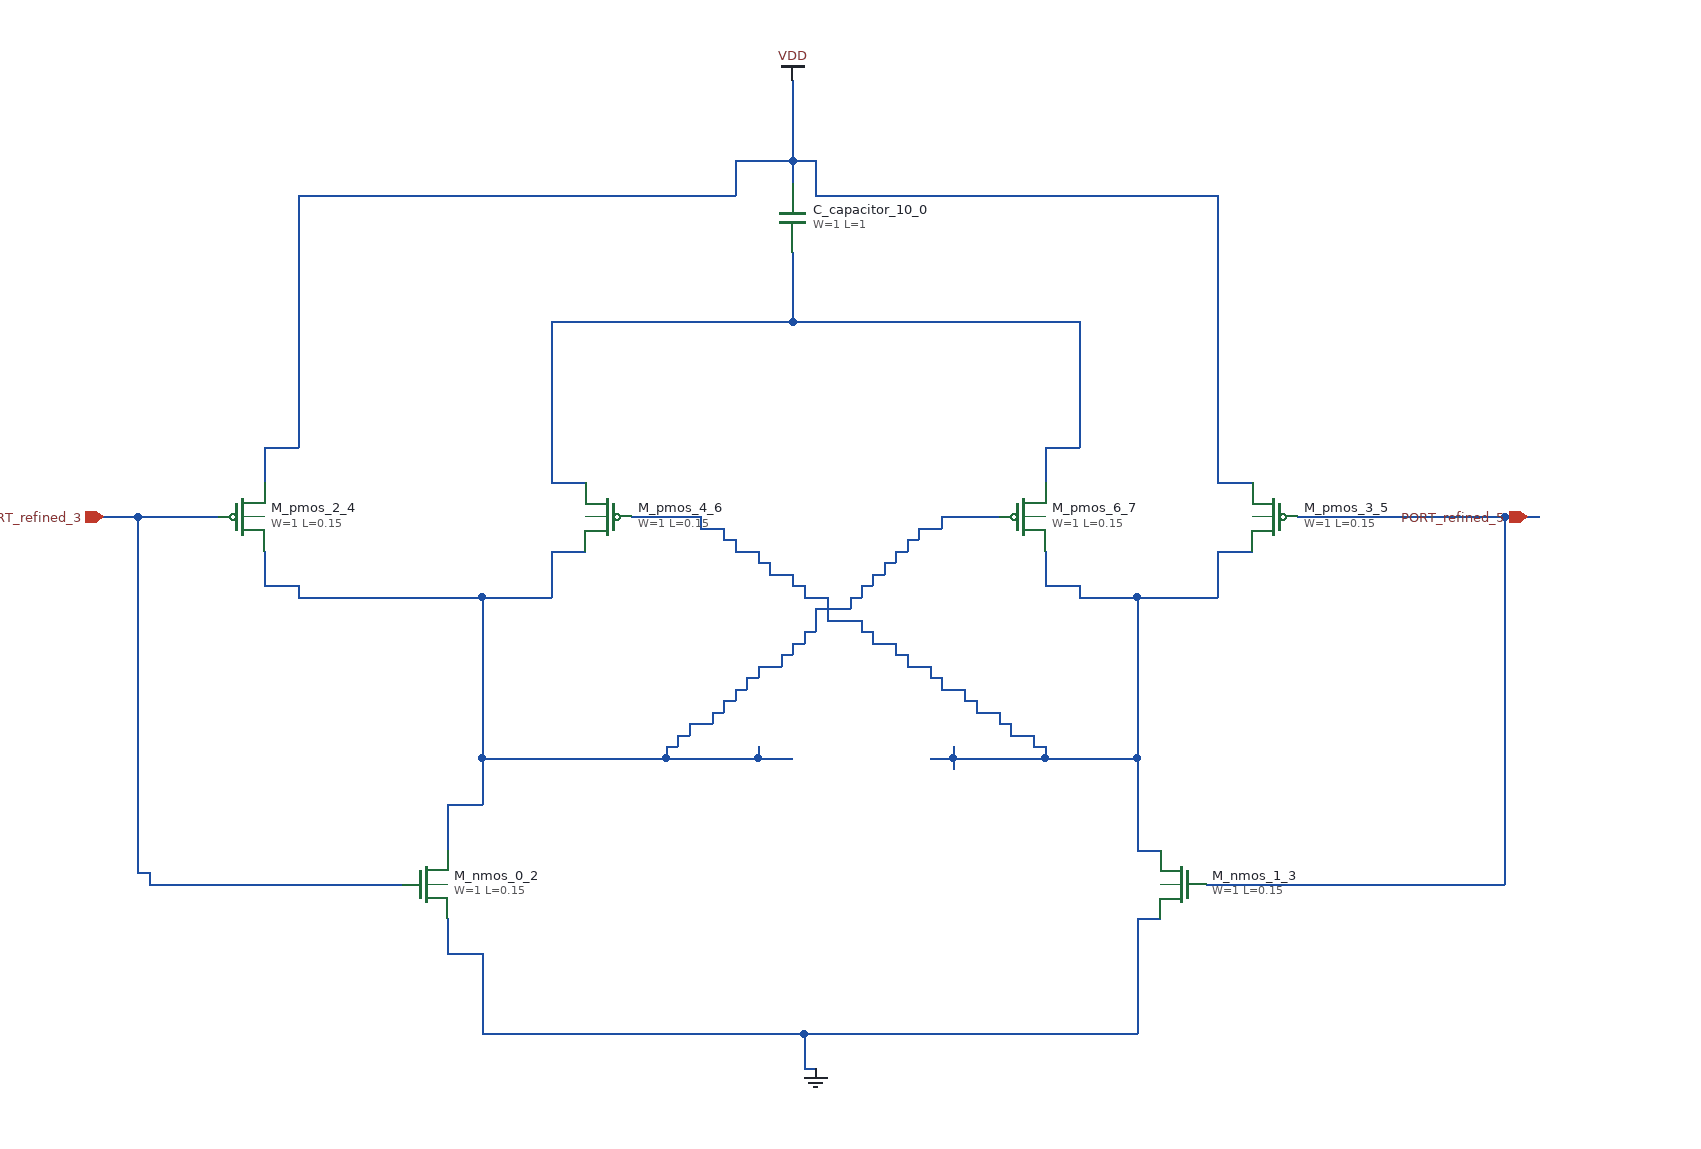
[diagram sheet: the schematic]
v {xschem version=3.4.8 file_version=1.2}
G {}
K {}
V {}
S {}
E {}
C {sky130_fd_pr/cap_mim_m3_1.sym} 680 200 2 0 {name="C_capacitor_10_0" model=cap_mim_m3_1 W=1 L=1 MF=1 spiceprefix=X}
C {devices/gnd.sym} 700 940 0 0 {name="l_gnd_5_1" lab="GND"}
C {sky130_fd_pr/nfet3_01v8.sym} 360 780 0 0 {name="M_nmos_0_2"
W=1
L=0.15
body=GND
nf=1
mult=1
ad="expr('int((@nf + 1)/2) * @W / @nf * 0.29')"
pd="expr('2*int((@nf + 1)/2) * (@W / @nf + 0.29)')"
as="expr('int((@nf + 2)/2) * @W / @nf * 0.29')"
ps="expr('2*int((@nf + 2)/2) * (@W / @nf + 0.29)')"
nrd="expr('0.29 / @W ')" nrs="expr('0.29 / @W ')"
sa=0 sb=0 sd=0
model=nfet_01v8
spiceprefix=X
}
C {sky130_fd_pr/nfet3_01v8.sym} 1020 780 0 1 {name="M_nmos_1_3"
W=1
L=0.15
body=GND
nf=1
mult=1
ad="expr('int((@nf + 1)/2) * @W / @nf * 0.29')"
pd="expr('2*int((@nf + 1)/2) * (@W / @nf + 0.29)')"
as="expr('int((@nf + 2)/2) * @W / @nf * 0.29')"
ps="expr('2*int((@nf + 2)/2) * (@W / @nf + 0.29)')"
nrd="expr('0.29 / @W ')" nrs="expr('0.29 / @W ')"
sa=0 sb=0 sd=0
model=nfet_01v8
spiceprefix=X
}
C {sky130_fd_pr/pfet3_01v8.sym} 200 460 0 0 {name="M_pmos_2_4"
W=1
L=0.15
body=VDD
nf=1
mult=1
ad="expr('int((@nf + 1)/2) * @W / @nf * 0.29')"
pd="expr('2*int((@nf + 1)/2) * (@W / @nf + 0.29)')"
as="expr('int((@nf + 2)/2) * @W / @nf * 0.29')"
ps="expr('2*int((@nf + 2)/2) * (@W / @nf + 0.29)')"
nrd="expr('0.29 / @W ')" nrs="expr('0.29 / @W ')"
sa=0 sb=0 sd=0
model=pfet_01v8
spiceprefix=X
}
C {sky130_fd_pr/pfet3_01v8.sym} 1100 460 0 1 {name="M_pmos_3_5"
W=1
L=0.15
body=VDD
nf=1
mult=1
ad="expr('int((@nf + 1)/2) * @W / @nf * 0.29')"
pd="expr('2*int((@nf + 1)/2) * (@W / @nf + 0.29)')"
as="expr('int((@nf + 2)/2) * @W / @nf * 0.29')"
ps="expr('2*int((@nf + 2)/2) * (@W / @nf + 0.29)')"
nrd="expr('0.29 / @W ')" nrs="expr('0.29 / @W ')"
sa=0 sb=0 sd=0
model=pfet_01v8
spiceprefix=X
}
C {sky130_fd_pr/pfet3_01v8.sym} 520 460 0 1 {name="M_pmos_4_6"
W=1
L=0.15
body=VDD
nf=1
mult=1
ad="expr('int((@nf + 1)/2) * @W / @nf * 0.29')"
pd="expr('2*int((@nf + 1)/2) * (@W / @nf + 0.29)')"
as="expr('int((@nf + 2)/2) * @W / @nf * 0.29')"
ps="expr('2*int((@nf + 2)/2) * (@W / @nf + 0.29)')"
nrd="expr('0.29 / @W ')" nrs="expr('0.29 / @W ')"
sa=0 sb=0 sd=0
model=pfet_01v8
spiceprefix=X
}
C {sky130_fd_pr/pfet3_01v8.sym} 880 460 0 0 {name="M_pmos_6_7"
W=1
L=0.15
body=VDD
nf=1
mult=1
ad="expr('int((@nf + 1)/2) * @W / @nf * 0.29')"
pd="expr('2*int((@nf + 1)/2) * (@W / @nf + 0.29)')"
as="expr('int((@nf + 2)/2) * @W / @nf * 0.29')"
ps="expr('2*int((@nf + 2)/2) * (@W / @nf + 0.29)')"
nrd="expr('0.29 / @W ')" nrs="expr('0.29 / @W ')"
sa=0 sb=0 sd=0
model=pfet_01v8
spiceprefix=X
}
C {devices/ipin.sym} 80 460 0 0 {name="p_port_7_8" lab="PORT_refined_3"}
C {devices/ipin.sym} 1320 460 0 0 {name="p_port_8_9" lab="PORT_refined_5"}
C {devices/vdd.sym} 680 80 0 0 {name="l_vdd_9_10" lab="VDD"}
N 1050 430 1080 430 {}
N 220 400 250 400 {}
N 250 180 630 180 {}
N 700 180 1050 180 {}
N 630 150 680 150 {}
N 680 150 700 150 {}
N 220 430 220 400 {}
N 250 400 250 180 {}
N 630 180 630 150 {}
N 680 170 680 150 {}
N 680 150 680 80 {}
N 700 180 700 150 {}
N 1050 430 1050 180 {}
N 470 430 500 430 {}
N 900 400 930 400 {}
N 470 290 680 290 {}
N 680 290 930 290 {}
N 470 430 470 290 {}
N 680 290 680 230 {}
N 900 430 900 400 {}
N 930 400 930 290 {}
N 380 710 410 710 {}
N 410 670 570 670 {}
N 570 670 650 670 {}
N 650 670 680 670 {}
N 570 660 580 660 {}
N 580 650 590 650 {}
N 590 640 610 640 {}
N 610 630 620 630 {}
N 620 620 630 620 {}
N 630 610 640 610 {}
N 640 600 650 600 {}
N 650 590 670 590 {}
N 670 580 680 580 {}
N 680 570 690 570 {}
N 690 560 700 560 {}
N 700 540 730 540 {}
N 250 530 410 530 {}
N 410 530 470 530 {}
N 730 530 740 530 {}
N 220 520 250 520 {}
N 740 520 750 520 {}
N 750 510 760 510 {}
N 760 500 770 500 {}
N 470 490 500 490 {}
N 770 490 780 490 {}
N 780 480 790 480 {}
N 790 470 810 470 {}
N 810 460 860 460 {}
N 220 520 220 490 {}
N 250 530 250 520 {}
N 380 750 380 710 {}
N 410 710 410 670 {}
N 410 670 410 530 {}
N 470 530 470 490 {}
N 570 670 570 660 {}
N 580 660 580 650 {}
N 590 650 590 640 {}
N 610 640 610 630 {}
N 620 630 620 620 {}
N 630 620 630 610 {}
N 640 610 640 600 {}
N 650 670 650 660 {}
N 650 600 650 590 {}
N 670 590 670 580 {}
N 680 580 680 570 {}
N 690 570 690 560 {}
N 700 560 700 540 {}
N 730 540 730 530 {}
N 740 530 740 520 {}
N 750 520 750 510 {}
N 760 510 760 500 {}
N 770 500 770 490 {}
N 780 490 780 480 {}
N 790 480 790 470 {}
N 810 470 810 460 {}
N 120 780 340 780 {}
N 110 770 120 770 {}
N 80 460 110 460 {}
N 110 460 180 460 {}
N 110 770 110 460 {}
N 120 780 120 770 {}
N 980 750 1000 750 {}
N 800 670 820 670 {}
N 820 670 900 670 {}
N 900 670 980 670 {}
N 890 660 900 660 {}
N 870 650 890 650 {}
N 860 640 870 640 {}
N 840 630 860 630 {}
N 830 620 840 620 {}
N 810 610 830 610 {}
N 800 600 810 600 {}
N 780 590 800 590 {}
N 770 580 780 580 {}
N 750 570 770 570 {}
N 740 560 750 560 {}
N 710 550 740 550 {}
N 690 530 710 530 {}
N 930 530 980 530 {}
N 980 530 1050 530 {}
N 680 520 690 520 {}
N 900 520 930 520 {}
N 660 510 680 510 {}
N 650 500 660 500 {}
N 630 490 650 490 {}
N 1050 490 1080 490 {}
N 620 480 630 480 {}
N 600 470 620 470 {}
N 540 460 600 460 {}
N 600 470 600 460 {}
N 620 480 620 470 {}
N 630 490 630 480 {}
N 650 500 650 490 {}
N 660 510 660 500 {}
N 680 520 680 510 {}
N 690 530 690 520 {}
N 710 550 710 530 {}
N 740 560 740 550 {}
N 750 570 750 560 {}
N 770 580 770 570 {}
N 780 590 780 580 {}
N 800 600 800 590 {}
N 810 610 810 600 {}
N 820 680 820 670 {}
N 820 670 820 660 {}
N 830 620 830 610 {}
N 840 630 840 620 {}
N 860 640 860 630 {}
N 870 650 870 640 {}
N 890 660 890 650 {}
N 900 670 900 660 {}
N 900 520 900 490 {}
N 930 530 930 520 {}
N 980 750 980 670 {}
N 980 670 980 530 {}
N 1050 530 1050 490 {}
N 1040 780 1300 780 {}
N 1120 460 1300 460 {}
N 1300 460 1320 460 {}
N 1320 460 1330 460 {}
N 1300 780 1300 460 {}
N 690 940 700 940 {}
N 410 910 690 910 {}
N 690 910 980 910 {}
N 380 840 410 840 {}
N 980 810 1000 810 {}
N 380 840 380 810 {}
N 410 910 410 840 {}
N 690 940 690 910 {}
N 980 910 980 810 {}
